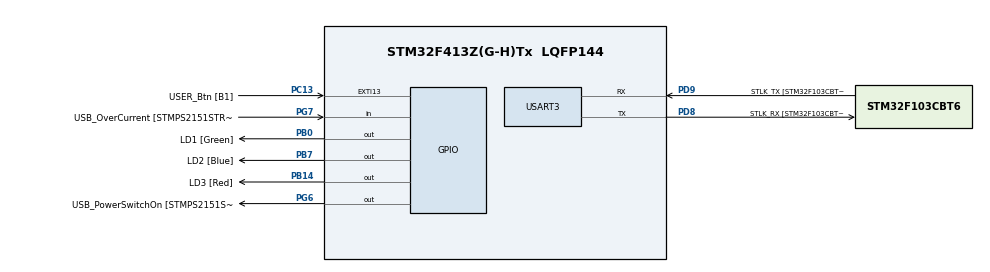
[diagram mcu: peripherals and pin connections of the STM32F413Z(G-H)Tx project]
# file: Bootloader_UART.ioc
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Dma.Request0=USART3_RX
Dma.USART3_RX.0.Direction=DMA_PERIPH_TO_MEMORY
Dma.USART3_RX.0.FIFOMode=DMA_FIFOMODE_ENABLE
Dma.USART3_RX.0.FIFOThreshold=DMA_FIFO_THRESHOLD_FULL
Dma.USART3_RX.0.Instance=DMA1_Stream1
Dma.USART3_RX.0.MemBurst=DMA_MBURST_SINGLE
Dma.USART3_RX.0.MemDataAlignment=DMA_MDATAALIGN_BYTE
Dma.USART3_RX.0.MemInc=DMA_MINC_ENABLE
Dma.USART3_RX.0.Mode=DMA_NORMAL
Dma.USART3_RX.0.PeriphBurst=DMA_PBURST_SINGLE
Dma.USART3_RX.0.PeriphDataAlignment=DMA_PDATAALIGN_BYTE
Dma.USART3_RX.0.PeriphInc=DMA_PINC_DISABLE
Dma.USART3_RX.0.Priority=DMA_PRIORITY_LOW
Mcu.Family=STM32F4
Mcu.Name=STM32F413Z(G-H)Tx
Mcu.Package=LQFP144
NVIC.DMA1_Stream1_IRQn=true\:0\:0\:false\:false\:true\:false\:true\:true
NVIC.PriorityGroup=NVIC_PRIORITYGROUP_4
PA10.GPIO_Label=USB_ID
PA10.Signal=USB_OTG_FS_ID
PA11.GPIO_Label=USB_DM
PA11.Signal=USB_OTG_FS_DM
PA12.GPIO_Label=USB_DP
PA12.Signal=USB_OTG_FS_DP
PA13.GPIO_Label=TMS
PA13.Mode=Serial_Wire
PA13.Signal=SYS_JTMS-SWDIO
PA14.GPIO_Label=TCK
PA14.Mode=Serial_Wire
PA14.Signal=SYS_JTCK-SWCLK
PA8.GPIO_Label=USB_SOF [TP1]
PA8.Signal=USB_OTG_FS_SOF
PA9.GPIO_Label=USB_VBUS
PA9.Signal=USB_OTG_FS_VBUS
PB0.GPIO_Label=LD1 [Green]
PB0.Signal=GPIO_Output
PB14.GPIO_Label=LD3 [Red]
PB14.Signal=GPIO_Output
PB3.Signal=SYS_JTDO-SWO
PB7.GPIO_Label=LD2 [Blue]
PB7.Signal=GPIO_Output
PC13.GPIO_Label=USER_Btn [B1]
PC13.Signal=GPXTI13
PC14-OSC32_IN.Signal=RCC_OSC32_IN
PC15-OSC32_OUT.Signal=RCC_OSC32_OUT
PD8.GPIO_Label=STLK_RX [STM32F103CBT6_PA3]
PD8.Mode=Asynchronous
PD8.Signal=USART3_TX
PD9.GPIO_Label=STLK_TX [STM32F103CBT6_PA2]
PD9.Mode=Asynchronous
PD9.Signal=USART3_RX
PG6.GPIO_Label=USB_PowerSwitchOn [STMPS2151STR_EN]
PG6.Signal=GPIO_Output
PG7.GPIO_Label=USB_OverCurrent [STMPS2151STR_FAULT]
PG7.Signal=GPIO_Input
PH0\ -\ OSC_IN.GPIO_Label=MCO
PH0\ -\ OSC_IN.Mode=HSE-External-Clock-Source
PH0\ -\ OSC_IN.Signal=RCC_OSC_IN
PH1\ -\ OSC_OUT.Mode=HSE-External-Clock-Source
PH1\ -\ OSC_OUT.Signal=RCC_OSC_OUT
ProjectManager.HeapSize=0x200
ProjectManager.StackSize=0x400
ProjectManager.TargetToolchain=CMake
RCC.48MHZClocksFreq_Value=24000000
RCC.AHBFreq_Value=48000000
RCC.APB1CLKDivider=RCC_HCLK_DIV2
RCC.APB1Freq_Value=24000000
RCC.APB1TimFreq_Value=48000000
RCC.APB2Freq_Value=48000000
RCC.APB2TimFreq_Value=48000000
RCC.CortexFreq_Value=48000000
RCC.HCLKFreq_Value=48000000
RCC.HSE_VALUE=48000000
RCC.HSI_VALUE=16000000
RCC.PLLM=8
RCC.PLLMUL=RCC_PLL_MUL9
RCC.PLLP=RCC_PLLP_DIV8
RCC.PRESCALERUSB=RCC_USBCLKSOURCE_PLL_DIV1_5
RCC.SYSCLKFreq_VALUE=48000000
RCC.SYSCLKSource=RCC_SYSCLKSOURCE_HSE
RCC.SYSCLKSourceVirtual=RCC_SYSCLKSOURCE_PLLCLK
RCC.USBFreq_Value=192000000
RCC.VCOOutputFreq_Value=384000000
USART3.VirtualMode=VM_ASYNC
board=NUCLEO-F413ZH

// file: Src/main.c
/* USER CODE BEGIN Header */
/**
  ******************************************************************************
  * @file           : main.c
  * @brief          : Main program body
  ******************************************************************************
  * @attention
  *
  * Copyright (c) 2026 STMicroelectronics.
  * All rights reserved.
  *
  * This software is licensed under terms that can be found in the LICENSE file
  * in the root directory of this software component.
  * If no LICENSE file comes with this software, it is provided AS-IS.
  *
  ******************************************************************************
  */
/* USER CODE END Header */
#include <string.h>
#include "main.h"
#include "stm32f413xx.h"

UART_HandleTypeDef huart3;
DMA_HandleTypeDef hdma_usart3_rx;

void SystemClock_Config(void);
static void MX_GPIO_Init(void);
static void MX_DMA_Init(void);
static void MX_USART3_UART_Init(void);

int main(void)
{

  /* MCU Configuration--------------------------------------------------------*/

  /* Reset of all peripherals, Initializes the Flash interface and the Systick. */
   HAL_Init();

  /* Configure the system clock */
  SystemClock_Config();

  /* Initialize all configured peripherals */
  MX_GPIO_Init();
  MX_DMA_Init();
  MX_USART3_UART_Init();
  /* USER CODE BEGIN 2 */
  // char *buf = "I am testing UART transmit message. Nothing more than that\r\n";
  char test_buf[] = "I am testing UART transmit message\r\n";

  /* USER CODE END 2 */

  /* Infinite loop */
  while (1)
  {
    HAL_GPIO_TogglePin( GPIOB, GPIO_PIN_0);
    HAL_Delay(1000);
    // HAL_UART_Transmit(&huart3, (uint8_t *)buf, strlen(buf), HAL_MAX_DELAY);
    HAL_UART_Transmit(&huart3, (uint8_t *)test_buf, sizeof(test_buf) - 1U, HAL_MAX_DELAY);
  }
}

void SystemClock_Config(void)
{
  RCC_OscInitTypeDef RCC_OscInitStruct = {0};
  RCC_ClkInitTypeDef RCC_ClkInitStruct = {0};

  /** Configure the main internal regulator output voltage
  */
  __HAL_RCC_PWR_CLK_ENABLE();
  __HAL_PWR_VOLTAGESCALING_CONFIG(PWR_REGULATOR_VOLTAGE_SCALE1);

  /** Initializes the RCC Oscillators according to the specified parameters
  * in the RCC_OscInitTypeDef structure.
  */
  // RCC_OscInitStruct.OscillatorType = RCC_OSCILLATORTYPE_HSE;
  // RCC_OscInitStruct.HSEState = RCC_HSE_BYPASS;
  // RCC_OscInitStruct.PLL.PLLState = RCC_PLL_NONE;
  RCC_OscInitStruct.OscillatorType = RCC_OSCILLATORTYPE_HSI;
  RCC_OscInitStruct.HSIState = RCC_HSI_ON;
  RCC_OscInitStruct.HSICalibrationValue = RCC_HSICALIBRATION_DEFAULT;
  RCC_OscInitStruct.PLL.PLLState = RCC_PLL_NONE;
  if (HAL_RCC_OscConfig(&RCC_OscInitStruct) != HAL_OK)
  {
    Error_Handler();
  }

  /** Initializes the CPU, AHB and APB buses clocks
  */
  RCC_ClkInitStruct.ClockType = RCC_CLOCKTYPE_HCLK|RCC_CLOCKTYPE_SYSCLK
                              |RCC_CLOCKTYPE_PCLK1|RCC_CLOCKTYPE_PCLK2;
  RCC_ClkInitStruct.SYSCLKSource = RCC_SYSCLKSOURCE_HSI;
  RCC_ClkInitStruct.AHBCLKDivider = RCC_SYSCLK_DIV1;
  RCC_ClkInitStruct.APB1CLKDivider = RCC_HCLK_DIV2;
  RCC_ClkInitStruct.APB2CLKDivider = RCC_HCLK_DIV1;

  if (HAL_RCC_ClockConfig(&RCC_ClkInitStruct, FLASH_LATENCY_1) != HAL_OK)
  {
    Error_Handler();
  }
}

static void MX_USART3_UART_Init(void)
{

  huart3.Instance = USART3;
  huart3.Init.BaudRate = 115200;
  huart3.Init.WordLength = UART_WORDLENGTH_8B;
  huart3.Init.StopBits = UART_STOPBITS_1;
  huart3.Init.Parity = UART_PARITY_NONE;
  huart3.Init.Mode = UART_MODE_TX_RX;
  huart3.Init.HwFlowCtl = UART_HWCONTROL_NONE;
  huart3.Init.OverSampling = UART_OVERSAMPLING_16;
  if (HAL_UART_Init(&huart3) != HAL_OK)
  {
    Error_Handler();
  }

}

static void MX_DMA_Init(void)
{

  /* DMA controller clock enable */
  __HAL_RCC_DMA1_CLK_ENABLE();

  /* DMA interrupt init */
  /* DMA1_Stream1_IRQn interrupt configuration */
  HAL_NVIC_SetPriority(DMA1_Stream1_IRQn, 0, 0);
  HAL_NVIC_EnableIRQ(DMA1_Stream1_IRQn);

}

static void MX_GPIO_Init(void)
{
  GPIO_InitTypeDef GPIO_InitStruct = {0};

  /* GPIO Ports Clock Enable */
  __HAL_RCC_GPIOC_CLK_ENABLE();
  __HAL_RCC_GPIOH_CLK_ENABLE();
  __HAL_RCC_GPIOB_CLK_ENABLE();
  __HAL_RCC_GPIOD_CLK_ENABLE();
  __HAL_RCC_GPIOG_CLK_ENABLE();
  __HAL_RCC_GPIOA_CLK_ENABLE();

  /*Configure GPIO pin Output Level */
  HAL_GPIO_WritePin(GPIOB, LD1_Pin|LD3_Pin|LD2_Pin, GPIO_PIN_RESET);

  /*Configure GPIO pin Output Level */
  HAL_GPIO_WritePin(USB_PowerSwitchOn_GPIO_Port, USB_PowerSwitchOn_Pin, GPIO_PIN_RESET);

  /*Configure GPIO pin : USER_Btn_Pin */
  GPIO_InitStruct.Pin = USER_Btn_Pin;
  GPIO_InitStruct.Mode = GPIO_MODE_IT_RISING;
  GPIO_InitStruct.Pull = GPIO_NOPULL;
  HAL_GPIO_Init(USER_Btn_GPIO_Port, &GPIO_InitStruct);

  /*Configure GPIO pins : LD1_Pin LD3_Pin LD2_Pin */
  GPIO_InitStruct.Pin = LD1_Pin|LD3_Pin|LD2_Pin;
  GPIO_InitStruct.Mode = GPIO_MODE_OUTPUT_PP;
  GPIO_InitStruct.Pull = GPIO_NOPULL;
  GPIO_InitStruct.Speed = GPIO_SPEED_FREQ_LOW;
  HAL_GPIO_Init(GPIOB, &GPIO_InitStruct);

  /*Configure GPIO pin : USB_PowerSwitchOn_Pin */
  GPIO_InitStruct.Pin = USB_PowerSwitchOn_Pin;
  GPIO_InitStruct.Mode = GPIO_MODE_OUTPUT_PP;
  GPIO_InitStruct.Pull = GPIO_NOPULL;
  GPIO_InitStruct.Speed = GPIO_SPEED_FREQ_LOW;
  HAL_GPIO_Init(USB_PowerSwitchOn_GPIO_Port, &GPIO_InitStruct);

  /*Configure GPIO pin : USB_OverCurrent_Pin */
  GPIO_InitStruct.Pin = USB_OverCurrent_Pin;
  GPIO_InitStruct.Mode = GPIO_MODE_INPUT;
  GPIO_InitStruct.Pull = GPIO_NOPULL;
  HAL_GPIO_Init(USB_OverCurrent_GPIO_Port, &GPIO_InitStruct);

  /*Configure GPIO pins : USB_SOF_Pin USB_ID_Pin USB_DM_Pin USB_DP_Pin */
  GPIO_InitStruct.Pin = USB_SOF_Pin|USB_ID_Pin|USB_DM_Pin|USB_DP_Pin;
  GPIO_InitStruct.Mode = GPIO_MODE_AF_PP;
  GPIO_InitStruct.Pull = GPIO_NOPULL;
  GPIO_InitStruct.Speed = GPIO_SPEED_FREQ_VERY_HIGH;
  GPIO_InitStruct.Alternate = GPIO_AF10_OTG_FS;
  HAL_GPIO_Init(GPIOA, &GPIO_InitStruct);

}

void Error_Handler(void)
{
  __disable_irq();
  while (1)
  {
  }
}
